VERSION 5.8 ;
BUSBITCHARS "[]" ;
DIVIDERCHAR "/" ;
UNITS
    DATABASE MICRONS 1000 ;
END UNITS

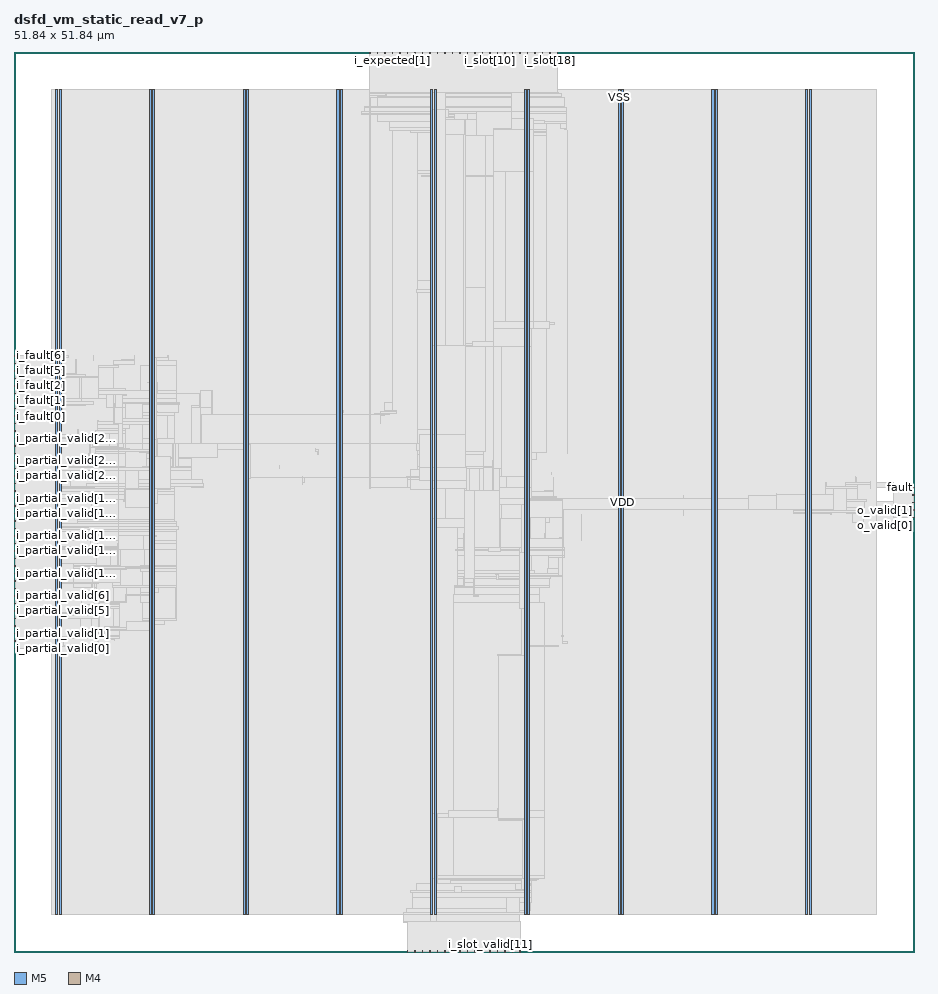
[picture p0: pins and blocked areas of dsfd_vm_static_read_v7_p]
MACRO dsfd_vm_static_read_v7_p
  FOREIGN dsfd_vm_static_read_v7_p 0 0 ;
  CLASS BLOCK ;
  SIZE 51.84 BY 51.84 ;
  PIN ck
    DIRECTION INPUT ;
    USE SIGNAL ;
    PORT
      LAYER M5 ;
        RECT  20.496 51.756 20.52 51.84 ;
    END
  END ck
  PIN fault
    DIRECTION OUTPUT ;
    USE SIGNAL ;
    PORT
      LAYER M4 ;
        RECT  51.756 26.736 51.84 26.76 ;
    END
  END fault
  PIN i_expected[0]
    DIRECTION INPUT ;
    USE SIGNAL ;
    PORT
      LAYER M5 ;
        RECT  21.36 51.756 21.384 51.84 ;
    END
  END i_expected[0]
  PIN i_expected[1]
    DIRECTION INPUT ;
    USE SIGNAL ;
    PORT
      LAYER M5 ;
        RECT  21.792 51.756 21.816 51.84 ;
    END
  END i_expected[1]
  PIN i_expected[2]
    DIRECTION INPUT ;
    USE SIGNAL ;
    PORT
      LAYER M5 ;
        RECT  22.224 51.756 22.248 51.84 ;
    END
  END i_expected[2]
  PIN i_expected[3]
    DIRECTION INPUT ;
    USE SIGNAL ;
    PORT
      LAYER M5 ;
        RECT  22.656 51.756 22.68 51.84 ;
    END
  END i_expected[3]
  PIN i_fault[0]
    DIRECTION INPUT ;
    USE SIGNAL ;
    PORT
      LAYER M4 ;
        RECT  0 31.296 0.084 31.32 ;
    END
  END i_fault[0]
  PIN i_fault[1]
    DIRECTION INPUT ;
    USE SIGNAL ;
    PORT
      LAYER M4 ;
        RECT  0 31.728 0.084 31.752 ;
    END
  END i_fault[1]
  PIN i_fault[2]
    DIRECTION INPUT ;
    USE SIGNAL ;
    PORT
      LAYER M4 ;
        RECT  0 32.16 0.084 32.184 ;
    END
  END i_fault[2]
  PIN i_fault[3]
    DIRECTION INPUT ;
    USE SIGNAL ;
    PORT
      LAYER M4 ;
        RECT  0 32.592 0.084 32.616 ;
    END
  END i_fault[3]
  PIN i_fault[4]
    DIRECTION INPUT ;
    USE SIGNAL ;
    PORT
      LAYER M4 ;
        RECT  0 33.024 0.084 33.048 ;
    END
  END i_fault[4]
  PIN i_fault[5]
    DIRECTION INPUT ;
    USE SIGNAL ;
    PORT
      LAYER M4 ;
        RECT  0 33.456 0.084 33.48 ;
    END
  END i_fault[5]
  PIN i_fault[6]
    DIRECTION INPUT ;
    USE SIGNAL ;
    PORT
      LAYER M4 ;
        RECT  0 33.888 0.084 33.912 ;
    END
  END i_fault[6]
  PIN i_fault[7]
    DIRECTION INPUT ;
    USE SIGNAL ;
    PORT
      LAYER M4 ;
        RECT  0 34.32 0.084 34.344 ;
    END
  END i_fault[7]
  PIN i_partial_valid[0]
    DIRECTION INPUT ;
    USE SIGNAL ;
    PORT
      LAYER M4 ;
        RECT  0 17.472 0.084 17.496 ;
    END
  END i_partial_valid[0]
  PIN i_partial_valid[10]
    DIRECTION INPUT ;
    USE SIGNAL ;
    PORT
      LAYER M4 ;
        RECT  0 21.792 0.084 21.816 ;
    END
  END i_partial_valid[10]
  PIN i_partial_valid[11]
    DIRECTION INPUT ;
    USE SIGNAL ;
    PORT
      LAYER M4 ;
        RECT  0 22.224 0.084 22.248 ;
    END
  END i_partial_valid[11]
  PIN i_partial_valid[12]
    DIRECTION INPUT ;
    USE SIGNAL ;
    PORT
      LAYER M4 ;
        RECT  0 22.656 0.084 22.68 ;
    END
  END i_partial_valid[12]
  PIN i_partial_valid[13]
    DIRECTION INPUT ;
    USE SIGNAL ;
    PORT
      LAYER M4 ;
        RECT  0 23.088 0.084 23.112 ;
    END
  END i_partial_valid[13]
  PIN i_partial_valid[14]
    DIRECTION INPUT ;
    USE SIGNAL ;
    PORT
      LAYER M4 ;
        RECT  0 23.52 0.084 23.544 ;
    END
  END i_partial_valid[14]
  PIN i_partial_valid[15]
    DIRECTION INPUT ;
    USE SIGNAL ;
    PORT
      LAYER M4 ;
        RECT  0 23.952 0.084 23.976 ;
    END
  END i_partial_valid[15]
  PIN i_partial_valid[16]
    DIRECTION INPUT ;
    USE SIGNAL ;
    PORT
      LAYER M4 ;
        RECT  0 24.384 0.084 24.408 ;
    END
  END i_partial_valid[16]
  PIN i_partial_valid[17]
    DIRECTION INPUT ;
    USE SIGNAL ;
    PORT
      LAYER M4 ;
        RECT  0 24.816 0.084 24.84 ;
    END
  END i_partial_valid[17]
  PIN i_partial_valid[18]
    DIRECTION INPUT ;
    USE SIGNAL ;
    PORT
      LAYER M4 ;
        RECT  0 25.248 0.084 25.272 ;
    END
  END i_partial_valid[18]
  PIN i_partial_valid[19]
    DIRECTION INPUT ;
    USE SIGNAL ;
    PORT
      LAYER M4 ;
        RECT  0 25.68 0.084 25.704 ;
    END
  END i_partial_valid[19]
  PIN i_partial_valid[1]
    DIRECTION INPUT ;
    USE SIGNAL ;
    PORT
      LAYER M4 ;
        RECT  0 17.904 0.084 17.928 ;
    END
  END i_partial_valid[1]
  PIN i_partial_valid[20]
    DIRECTION INPUT ;
    USE SIGNAL ;
    PORT
      LAYER M4 ;
        RECT  0 26.112 0.084 26.136 ;
    END
  END i_partial_valid[20]
  PIN i_partial_valid[21]
    DIRECTION INPUT ;
    USE SIGNAL ;
    PORT
      LAYER M4 ;
        RECT  0 26.544 0.084 26.568 ;
    END
  END i_partial_valid[21]
  PIN i_partial_valid[22]
    DIRECTION INPUT ;
    USE SIGNAL ;
    PORT
      LAYER M4 ;
        RECT  0 26.976 0.084 27 ;
    END
  END i_partial_valid[22]
  PIN i_partial_valid[23]
    DIRECTION INPUT ;
    USE SIGNAL ;
    PORT
      LAYER M4 ;
        RECT  0 27.408 0.084 27.432 ;
    END
  END i_partial_valid[23]
  PIN i_partial_valid[24]
    DIRECTION INPUT ;
    USE SIGNAL ;
    PORT
      LAYER M4 ;
        RECT  0 27.84 0.084 27.864 ;
    END
  END i_partial_valid[24]
  PIN i_partial_valid[25]
    DIRECTION INPUT ;
    USE SIGNAL ;
    PORT
      LAYER M4 ;
        RECT  0 28.272 0.084 28.296 ;
    END
  END i_partial_valid[25]
  PIN i_partial_valid[26]
    DIRECTION INPUT ;
    USE SIGNAL ;
    PORT
      LAYER M4 ;
        RECT  0 28.704 0.084 28.728 ;
    END
  END i_partial_valid[26]
  PIN i_partial_valid[27]
    DIRECTION INPUT ;
    USE SIGNAL ;
    PORT
      LAYER M4 ;
        RECT  0 29.136 0.084 29.16 ;
    END
  END i_partial_valid[27]
  PIN i_partial_valid[28]
    DIRECTION INPUT ;
    USE SIGNAL ;
    PORT
      LAYER M4 ;
        RECT  0 29.568 0.084 29.592 ;
    END
  END i_partial_valid[28]
  PIN i_partial_valid[29]
    DIRECTION INPUT ;
    USE SIGNAL ;
    PORT
      LAYER M4 ;
        RECT  0 30 0.084 30.024 ;
    END
  END i_partial_valid[29]
  PIN i_partial_valid[2]
    DIRECTION INPUT ;
    USE SIGNAL ;
    PORT
      LAYER M4 ;
        RECT  0 18.336 0.084 18.36 ;
    END
  END i_partial_valid[2]
  PIN i_partial_valid[30]
    DIRECTION INPUT ;
    USE SIGNAL ;
    PORT
      LAYER M4 ;
        RECT  0 30.432 0.084 30.456 ;
    END
  END i_partial_valid[30]
  PIN i_partial_valid[31]
    DIRECTION INPUT ;
    USE SIGNAL ;
    PORT
      LAYER M4 ;
        RECT  0 30.864 0.084 30.888 ;
    END
  END i_partial_valid[31]
  PIN i_partial_valid[3]
    DIRECTION INPUT ;
    USE SIGNAL ;
    PORT
      LAYER M4 ;
        RECT  0 18.768 0.084 18.792 ;
    END
  END i_partial_valid[3]
  PIN i_partial_valid[4]
    DIRECTION INPUT ;
    USE SIGNAL ;
    PORT
      LAYER M4 ;
        RECT  0 19.2 0.084 19.224 ;
    END
  END i_partial_valid[4]
  PIN i_partial_valid[5]
    DIRECTION INPUT ;
    USE SIGNAL ;
    PORT
      LAYER M4 ;
        RECT  0 19.632 0.084 19.656 ;
    END
  END i_partial_valid[5]
  PIN i_partial_valid[6]
    DIRECTION INPUT ;
    USE SIGNAL ;
    PORT
      LAYER M4 ;
        RECT  0 20.064 0.084 20.088 ;
    END
  END i_partial_valid[6]
  PIN i_partial_valid[7]
    DIRECTION INPUT ;
    USE SIGNAL ;
    PORT
      LAYER M4 ;
        RECT  0 20.496 0.084 20.52 ;
    END
  END i_partial_valid[7]
  PIN i_partial_valid[8]
    DIRECTION INPUT ;
    USE SIGNAL ;
    PORT
      LAYER M4 ;
        RECT  0 20.928 0.084 20.952 ;
    END
  END i_partial_valid[8]
  PIN i_partial_valid[9]
    DIRECTION INPUT ;
    USE SIGNAL ;
    PORT
      LAYER M4 ;
        RECT  0 21.36 0.084 21.384 ;
    END
  END i_partial_valid[9]
  PIN i_slot[0]
    DIRECTION INPUT ;
    USE SIGNAL ;
    PORT
      LAYER M5 ;
        RECT  23.088 51.756 23.112 51.84 ;
    END
  END i_slot[0]
  PIN i_slot[10]
    DIRECTION INPUT ;
    USE SIGNAL ;
    PORT
      LAYER M5 ;
        RECT  27.408 51.756 27.432 51.84 ;
    END
  END i_slot[10]
  PIN i_slot[11]
    DIRECTION INPUT ;
    USE SIGNAL ;
    PORT
      LAYER M5 ;
        RECT  27.84 51.756 27.864 51.84 ;
    END
  END i_slot[11]
  PIN i_slot[12]
    DIRECTION INPUT ;
    USE SIGNAL ;
    PORT
      LAYER M5 ;
        RECT  28.272 51.756 28.296 51.84 ;
    END
  END i_slot[12]
  PIN i_slot[13]
    DIRECTION INPUT ;
    USE SIGNAL ;
    PORT
      LAYER M5 ;
        RECT  28.704 51.756 28.728 51.84 ;
    END
  END i_slot[13]
  PIN i_slot[14]
    DIRECTION INPUT ;
    USE SIGNAL ;
    PORT
      LAYER M5 ;
        RECT  29.136 51.756 29.16 51.84 ;
    END
  END i_slot[14]
  PIN i_slot[15]
    DIRECTION INPUT ;
    USE SIGNAL ;
    PORT
      LAYER M5 ;
        RECT  29.568 51.756 29.592 51.84 ;
    END
  END i_slot[15]
  PIN i_slot[16]
    DIRECTION INPUT ;
    USE SIGNAL ;
    PORT
      LAYER M5 ;
        RECT  30 51.756 30.024 51.84 ;
    END
  END i_slot[16]
  PIN i_slot[17]
    DIRECTION INPUT ;
    USE SIGNAL ;
    PORT
      LAYER M5 ;
        RECT  30.432 51.756 30.456 51.84 ;
    END
  END i_slot[17]
  PIN i_slot[18]
    DIRECTION INPUT ;
    USE SIGNAL ;
    PORT
      LAYER M5 ;
        RECT  30.864 51.756 30.888 51.84 ;
    END
  END i_slot[18]
  PIN i_slot[19]
    DIRECTION INPUT ;
    USE SIGNAL ;
    PORT
      LAYER M5 ;
        RECT  31.296 51.756 31.32 51.84 ;
    END
  END i_slot[19]
  PIN i_slot[1]
    DIRECTION INPUT ;
    USE SIGNAL ;
    PORT
      LAYER M5 ;
        RECT  23.52 51.756 23.544 51.84 ;
    END
  END i_slot[1]
  PIN i_slot[2]
    DIRECTION INPUT ;
    USE SIGNAL ;
    PORT
      LAYER M5 ;
        RECT  23.952 51.756 23.976 51.84 ;
    END
  END i_slot[2]
  PIN i_slot[3]
    DIRECTION INPUT ;
    USE SIGNAL ;
    PORT
      LAYER M5 ;
        RECT  24.384 51.756 24.408 51.84 ;
    END
  END i_slot[3]
  PIN i_slot[4]
    DIRECTION INPUT ;
    USE SIGNAL ;
    PORT
      LAYER M5 ;
        RECT  24.816 51.756 24.84 51.84 ;
    END
  END i_slot[4]
  PIN i_slot[5]
    DIRECTION INPUT ;
    USE SIGNAL ;
    PORT
      LAYER M5 ;
        RECT  25.248 51.756 25.272 51.84 ;
    END
  END i_slot[5]
  PIN i_slot[6]
    DIRECTION INPUT ;
    USE SIGNAL ;
    PORT
      LAYER M5 ;
        RECT  25.68 51.756 25.704 51.84 ;
    END
  END i_slot[6]
  PIN i_slot[7]
    DIRECTION INPUT ;
    USE SIGNAL ;
    PORT
      LAYER M5 ;
        RECT  26.112 51.756 26.136 51.84 ;
    END
  END i_slot[7]
  PIN i_slot[8]
    DIRECTION INPUT ;
    USE SIGNAL ;
    PORT
      LAYER M5 ;
        RECT  26.544 51.756 26.568 51.84 ;
    END
  END i_slot[8]
  PIN i_slot[9]
    DIRECTION INPUT ;
    USE SIGNAL ;
    PORT
      LAYER M5 ;
        RECT  26.976 51.756 27 51.84 ;
    END
  END i_slot[9]
  PIN i_slot_valid[0]
    DIRECTION INPUT ;
    USE SIGNAL ;
    PORT
      LAYER M5 ;
        RECT  22.656 0 22.68 0.084 ;
    END
  END i_slot_valid[0]
  PIN i_slot_valid[10]
    DIRECTION INPUT ;
    USE SIGNAL ;
    PORT
      LAYER M5 ;
        RECT  26.976 0 27 0.084 ;
    END
  END i_slot_valid[10]
  PIN i_slot_valid[11]
    DIRECTION INPUT ;
    USE SIGNAL ;
    PORT
      LAYER M5 ;
        RECT  27.408 0 27.432 0.084 ;
    END
  END i_slot_valid[11]
  PIN i_slot_valid[12]
    DIRECTION INPUT ;
    USE SIGNAL ;
    PORT
      LAYER M5 ;
        RECT  27.84 0 27.864 0.084 ;
    END
  END i_slot_valid[12]
  PIN i_slot_valid[13]
    DIRECTION INPUT ;
    USE SIGNAL ;
    PORT
      LAYER M5 ;
        RECT  28.272 0 28.296 0.084 ;
    END
  END i_slot_valid[13]
  PIN i_slot_valid[14]
    DIRECTION INPUT ;
    USE SIGNAL ;
    PORT
      LAYER M5 ;
        RECT  28.704 0 28.728 0.084 ;
    END
  END i_slot_valid[14]
  PIN i_slot_valid[15]
    DIRECTION INPUT ;
    USE SIGNAL ;
    PORT
      LAYER M5 ;
        RECT  29.136 0 29.16 0.084 ;
    END
  END i_slot_valid[15]
  PIN i_slot_valid[1]
    DIRECTION INPUT ;
    USE SIGNAL ;
    PORT
      LAYER M5 ;
        RECT  23.088 0 23.112 0.084 ;
    END
  END i_slot_valid[1]
  PIN i_slot_valid[2]
    DIRECTION INPUT ;
    USE SIGNAL ;
    PORT
      LAYER M5 ;
        RECT  23.52 0 23.544 0.084 ;
    END
  END i_slot_valid[2]
  PIN i_slot_valid[3]
    DIRECTION INPUT ;
    USE SIGNAL ;
    PORT
      LAYER M5 ;
        RECT  23.952 0 23.976 0.084 ;
    END
  END i_slot_valid[3]
  PIN i_slot_valid[4]
    DIRECTION INPUT ;
    USE SIGNAL ;
    PORT
      LAYER M5 ;
        RECT  24.384 0 24.408 0.084 ;
    END
  END i_slot_valid[4]
  PIN i_slot_valid[5]
    DIRECTION INPUT ;
    USE SIGNAL ;
    PORT
      LAYER M5 ;
        RECT  24.816 0 24.84 0.084 ;
    END
  END i_slot_valid[5]
  PIN i_slot_valid[6]
    DIRECTION INPUT ;
    USE SIGNAL ;
    PORT
      LAYER M5 ;
        RECT  25.248 0 25.272 0.084 ;
    END
  END i_slot_valid[6]
  PIN i_slot_valid[7]
    DIRECTION INPUT ;
    USE SIGNAL ;
    PORT
      LAYER M5 ;
        RECT  25.68 0 25.704 0.084 ;
    END
  END i_slot_valid[7]
  PIN i_slot_valid[8]
    DIRECTION INPUT ;
    USE SIGNAL ;
    PORT
      LAYER M5 ;
        RECT  26.112 0 26.136 0.084 ;
    END
  END i_slot_valid[8]
  PIN i_slot_valid[9]
    DIRECTION INPUT ;
    USE SIGNAL ;
    PORT
      LAYER M5 ;
        RECT  26.544 0 26.568 0.084 ;
    END
  END i_slot_valid[9]
  PIN o_valid[0]
    DIRECTION OUTPUT ;
    USE SIGNAL ;
    PORT
      LAYER M4 ;
        RECT  51.756 25.008 51.84 25.032 ;
    END
  END o_valid[0]
  PIN o_valid[1]
    DIRECTION OUTPUT ;
    USE SIGNAL ;
    PORT
      LAYER M4 ;
        RECT  51.756 25.44 51.84 25.464 ;
    END
  END o_valid[1]
  PIN o_valid[2]
    DIRECTION OUTPUT ;
    USE SIGNAL ;
    PORT
      LAYER M4 ;
        RECT  51.756 25.872 51.84 25.896 ;
    END
  END o_valid[2]
  PIN o_valid[3]
    DIRECTION OUTPUT ;
    USE SIGNAL ;
    PORT
      LAYER M4 ;
        RECT  51.756 26.304 51.84 26.328 ;
    END
  END o_valid[3]
  PIN rst_n
    DIRECTION INPUT ;
    USE SIGNAL ;
    PORT
      LAYER M5 ;
        RECT  20.928 51.756 20.952 51.84 ;
    END
  END rst_n
  PIN VDD
    DIRECTION INOUT ;
    USE POWER ;
    PORT
      LAYER M5 ;
        RECT  45.792 2.151 45.912 49.689 ;
        RECT  40.392 2.151 40.512 49.689 ;
        RECT  34.992 2.151 35.112 49.689 ;
        RECT  29.592 2.151 29.712 49.689 ;
        RECT  24.192 2.151 24.312 49.689 ;
        RECT  18.792 2.151 18.912 49.689 ;
        RECT  13.392 2.151 13.512 49.689 ;
        RECT  7.992 2.151 8.112 49.689 ;
        RECT  2.592 2.151 2.712 49.689 ;
    END
  END VDD
  PIN VSS
    DIRECTION INOUT ;
    USE GROUND ;
    PORT
      LAYER M5 ;
        RECT  45.6 2.137 45.72 49.703 ;
        RECT  40.2 2.137 40.32 49.703 ;
        RECT  34.8 2.137 34.92 49.703 ;
        RECT  29.4 2.137 29.52 49.703 ;
        RECT  24 2.137 24.12 49.703 ;
        RECT  18.6 2.137 18.72 49.703 ;
        RECT  13.2 2.137 13.32 49.703 ;
        RECT  7.8 2.137 7.92 49.703 ;
        RECT  2.4 2.137 2.52 49.703 ;
    END
  END VSS
  # OT_OBS_CLOSED layer=M5 d_um=1.536 added=21
  OBS
    LAYER RVTN ;
     RECT  2.16 2.16 49.68 2.295 ;
     RECT  2.16 2.565 49.68 2.835 ;
     RECT  2.16 3.105 49.68 3.375 ;
     RECT  2.16 3.645 49.68 3.915 ;
     RECT  2.16 4.185 49.68 4.455 ;
     RECT  2.16 4.725 49.68 4.995 ;
     RECT  2.16 5.265 49.68 5.535 ;
     RECT  2.16 5.805 49.68 6.075 ;
     RECT  2.16 6.345 49.68 6.615 ;
     RECT  2.16 6.885 49.68 7.155 ;
     RECT  2.16 7.425 49.68 7.695 ;
     RECT  2.16 7.965 49.68 8.235 ;
     RECT  2.16 8.505 49.68 8.775 ;
     RECT  2.16 9.045 49.68 9.315 ;
     RECT  2.16 9.585 49.68 9.855 ;
     RECT  2.16 10.125 49.68 10.395 ;
     RECT  2.16 10.665 49.68 10.935 ;
     RECT  2.16 11.205 49.68 11.475 ;
     RECT  2.16 11.745 49.68 12.015 ;
     RECT  2.16 12.285 49.68 12.555 ;
     RECT  2.16 12.825 49.68 13.095 ;
     RECT  2.16 13.365 49.68 13.635 ;
     RECT  2.16 13.905 49.68 14.175 ;
     RECT  2.16 14.445 49.68 14.715 ;
     RECT  2.16 14.985 49.68 15.255 ;
     RECT  2.16 15.525 49.68 15.795 ;
     RECT  2.16 16.065 49.68 16.335 ;
     RECT  2.16 16.605 49.68 16.875 ;
     RECT  2.16 17.145 49.68 17.415 ;
     RECT  2.16 17.685 49.68 17.955 ;
     RECT  2.16 18.225 49.68 18.495 ;
     RECT  2.16 18.765 49.68 19.035 ;
     RECT  2.16 19.305 49.68 19.575 ;
     RECT  2.16 19.845 49.68 20.115 ;
     RECT  2.16 20.385 49.68 20.655 ;
     RECT  2.16 20.925 49.68 21.195 ;
     RECT  2.16 21.465 49.68 21.735 ;
     RECT  2.16 22.005 49.68 22.275 ;
     RECT  2.16 22.545 49.68 22.815 ;
     RECT  2.16 23.085 49.68 23.355 ;
     RECT  2.16 23.625 49.68 23.895 ;
     RECT  2.16 24.165 49.68 24.435 ;
     RECT  2.16 24.705 49.68 24.975 ;
     RECT  2.16 25.245 49.68 25.515 ;
     RECT  2.16 25.785 49.68 26.055 ;
     RECT  2.16 26.325 49.68 26.595 ;
     RECT  2.16 26.865 49.68 27.135 ;
     RECT  2.16 27.405 49.68 27.675 ;
     RECT  2.16 27.945 49.68 28.215 ;
     RECT  2.16 28.485 49.68 28.755 ;
     RECT  2.16 29.025 49.68 29.295 ;
     RECT  2.16 29.565 49.68 29.835 ;
     RECT  2.16 30.105 49.68 30.375 ;
     RECT  2.16 30.645 49.68 30.915 ;
     RECT  2.16 31.185 49.68 31.455 ;
     RECT  2.16 31.725 49.68 31.995 ;
     RECT  2.16 32.265 49.68 32.535 ;
     RECT  2.16 32.805 49.68 33.075 ;
     RECT  2.16 33.345 49.68 33.615 ;
     RECT  2.16 33.885 49.68 34.155 ;
     RECT  2.16 34.425 49.68 34.695 ;
     RECT  2.16 34.965 49.68 35.235 ;
     RECT  2.16 35.505 49.68 35.775 ;
     RECT  2.16 36.045 49.68 36.315 ;
     RECT  2.16 36.585 49.68 36.855 ;
     RECT  2.16 37.125 49.68 37.395 ;
     RECT  2.16 37.665 49.68 37.935 ;
     RECT  2.16 38.205 49.68 38.475 ;
     RECT  2.16 38.745 49.68 39.015 ;
     RECT  2.16 39.285 49.68 39.555 ;
     RECT  2.16 39.825 49.68 40.095 ;
     RECT  2.16 40.365 49.68 40.635 ;
     RECT  2.16 40.905 49.68 41.175 ;
     RECT  2.16 41.445 49.68 41.715 ;
     RECT  2.16 41.985 49.68 42.255 ;
     RECT  2.16 42.525 49.68 42.795 ;
     RECT  2.16 43.065 49.68 43.335 ;
     RECT  2.16 43.605 49.68 43.875 ;
     RECT  2.16 44.145 49.68 44.415 ;
     RECT  2.16 44.685 49.68 44.955 ;
     RECT  2.16 45.225 49.68 45.495 ;
     RECT  2.16 45.765 49.68 46.035 ;
     RECT  2.16 46.305 49.68 46.575 ;
     RECT  2.16 46.845 49.68 47.115 ;
     RECT  2.16 47.385 49.68 47.655 ;
     RECT  2.16 47.925 49.68 48.195 ;
     RECT  2.16 48.465 49.68 48.735 ;
     RECT  2.16 49.005 49.68 49.275 ;
     RECT  2.16 49.545 49.68 49.68 ;
    LAYER RVTP ;
     RECT  2.16 2.295 49.68 2.565 ;
     RECT  2.16 2.835 49.68 3.105 ;
     RECT  2.16 3.375 49.68 3.645 ;
     RECT  2.16 3.915 49.68 4.185 ;
     RECT  2.16 4.455 49.68 4.725 ;
     RECT  2.16 4.995 49.68 5.265 ;
     RECT  2.16 5.535 49.68 5.805 ;
     RECT  2.16 6.075 49.68 6.345 ;
     RECT  2.16 6.615 49.68 6.885 ;
     RECT  2.16 7.155 49.68 7.425 ;
     RECT  2.16 7.695 49.68 7.965 ;
     RECT  2.16 8.235 49.68 8.505 ;
     RECT  2.16 8.775 49.68 9.045 ;
     RECT  2.16 9.315 49.68 9.585 ;
     RECT  2.16 9.855 49.68 10.125 ;
     RECT  2.16 10.395 49.68 10.665 ;
     RECT  2.16 10.935 49.68 11.205 ;
     RECT  2.16 11.475 49.68 11.745 ;
     RECT  2.16 12.015 49.68 12.285 ;
     RECT  2.16 12.555 49.68 12.825 ;
     RECT  2.16 13.095 49.68 13.365 ;
     RECT  2.16 13.635 49.68 13.905 ;
     RECT  2.16 14.175 49.68 14.445 ;
     RECT  2.16 14.715 49.68 14.985 ;
     RECT  2.16 15.255 49.68 15.525 ;
     RECT  2.16 15.795 49.68 16.065 ;
     RECT  2.16 16.335 49.68 16.605 ;
     RECT  2.16 16.875 49.68 17.145 ;
     RECT  2.16 17.415 49.68 17.685 ;
     RECT  2.16 17.955 49.68 18.225 ;
     RECT  2.16 18.495 49.68 18.765 ;
     RECT  2.16 19.035 49.68 19.305 ;
     RECT  2.16 19.575 49.68 19.845 ;
     RECT  2.16 20.115 49.68 20.385 ;
     RECT  2.16 20.655 49.68 20.925 ;
     RECT  2.16 21.195 49.68 21.465 ;
     RECT  2.16 21.735 49.68 22.005 ;
     RECT  2.16 22.275 49.68 22.545 ;
     RECT  2.16 22.815 49.68 23.085 ;
     RECT  2.16 23.355 49.68 23.625 ;
     RECT  2.16 23.895 49.68 24.165 ;
     RECT  2.16 24.435 49.68 24.705 ;
     RECT  2.16 24.975 49.68 25.245 ;
     RECT  2.16 25.515 49.68 25.785 ;
     RECT  2.16 26.055 49.68 26.325 ;
     RECT  2.16 26.595 49.68 26.865 ;
     RECT  2.16 27.135 49.68 27.405 ;
     RECT  2.16 27.675 49.68 27.945 ;
     RECT  2.16 28.215 49.68 28.485 ;
     RECT  2.16 28.755 49.68 29.025 ;
     RECT  2.16 29.295 49.68 29.565 ;
     RECT  2.16 29.835 49.68 30.105 ;
     RECT  2.16 30.375 49.68 30.645 ;
     RECT  2.16 30.915 49.68 31.185 ;
     RECT  2.16 31.455 49.68 31.725 ;
     RECT  2.16 31.995 49.68 32.265 ;
     RECT  2.16 32.535 49.68 32.805 ;
     RECT  2.16 33.075 49.68 33.345 ;
     RECT  2.16 33.615 49.68 33.885 ;
     RECT  2.16 34.155 49.68 34.425 ;
     RECT  2.16 34.695 49.68 34.965 ;
     RECT  2.16 35.235 49.68 35.505 ;
     RECT  2.16 35.775 49.68 36.045 ;
     RECT  2.16 36.315 49.68 36.585 ;
     RECT  2.16 36.855 49.68 37.125 ;
     RECT  2.16 37.395 49.68 37.665 ;
     RECT  2.16 37.935 49.68 38.205 ;
     RECT  2.16 38.475 49.68 38.745 ;
     RECT  2.16 39.015 49.68 39.285 ;
     RECT  2.16 39.555 49.68 39.825 ;
     RECT  2.16 40.095 49.68 40.365 ;
     RECT  2.16 40.635 49.68 40.905 ;
     RECT  2.16 41.175 49.68 41.445 ;
     RECT  2.16 41.715 49.68 41.985 ;
     RECT  2.16 42.255 49.68 42.525 ;
     RECT  2.16 42.795 49.68 43.065 ;
     RECT  2.16 43.335 49.68 43.605 ;
     RECT  2.16 43.875 49.68 44.145 ;
     RECT  2.16 44.415 49.68 44.685 ;
     RECT  2.16 44.955 49.68 45.225 ;
     RECT  2.16 45.495 49.68 45.765 ;
     RECT  2.16 46.035 49.68 46.305 ;
     RECT  2.16 46.575 49.68 46.845 ;
     RECT  2.16 47.115 49.68 47.385 ;
     RECT  2.16 47.655 49.68 47.925 ;
     RECT  2.16 48.195 49.68 48.465 ;
     RECT  2.16 48.735 49.68 49.005 ;
     RECT  2.16 49.275 49.68 49.545 ;
    LAYER M1 ;
     RECT  2.16 2.151 49.68 49.689 ;
    LAYER M2 ;
     RECT  0.535 22.212 2.16 22.23 ;
     RECT  2.16 2.151 49.68 49.689 ;
     RECT  49.68 26.766 50.675 27.054 ;
     RECT  49.68 24.786 50.711 25.974 ;
     RECT  50.675 26.766 50.711 26.784 ;
    LAYER M3 ;
     RECT  23.94 0.571 23.958 1.723 ;
     RECT  25.668 0.571 25.686 1.723 ;
     RECT  22.428 1.723 29.142 2.143 ;
     RECT  22.428 2.143 29.505 2.255 ;
     RECT  29.088 2.255 29.505 2.371 ;
     RECT  2.415 2.143 2.505 2.413 ;
     RECT  7.815 2.143 7.905 2.413 ;
     RECT  13.215 2.143 13.305 2.413 ;
     RECT  18.615 2.143 18.705 2.413 ;
     RECT  34.815 2.143 34.905 2.413 ;
     RECT  40.215 2.143 40.305 2.413 ;
     RECT  45.615 2.143 45.705 2.413 ;
     RECT  22.608 2.255 28.35 2.489 ;
     RECT  29.088 2.371 29.754 2.839 ;
     RECT  22.932 2.489 28.35 3.145 ;
     RECT  29.088 2.839 29.826 3.145 ;
     RECT  22.932 3.145 29.826 3.451 ;
     RECT  22.824 3.451 29.826 3.569 ;
     RECT  23.184 3.569 29.826 3.947 ;
     RECT  23.616 3.947 29.826 3.965 ;
     RECT  24.015 3.965 29.826 4.117 ;
     RECT  24.015 4.117 30.078 4.153 ;
     RECT  24.015 4.153 30.186 4.261 ;
     RECT  24.015 4.261 30.546 4.415 ;
     RECT  25.308 4.415 30.546 7.723 ;
     RECT  25.02 7.723 30.546 8.159 ;
     RECT  2.415 2.413 2.697 17.455 ;
     RECT  2.304 17.455 2.697 17.501 ;
     RECT  2.415 17.501 2.697 17.608 ;
     RECT  4.428 17.581 4.446 17.611 ;
     RECT  4.428 17.611 4.842 17.617 ;
     RECT  31.356 17.608 31.374 17.645 ;
     RECT  2.415 17.608 3.294 17.653 ;
     RECT  4.068 17.617 4.842 17.653 ;
     RECT  31.572 17.761 31.878 17.879 ;
     RECT  5.796 17.959 5.814 17.995 ;
     RECT  2.415 17.653 4.842 18.031 ;
     RECT  5.616 17.995 5.814 18.031 ;
     RECT  2.415 18.031 6.066 18.185 ;
     RECT  3.816 18.185 6.066 18.221 ;
     RECT  31.572 17.879 31.59 18.221 ;
     RECT  2.415 18.185 2.697 18.331 ;
     RECT  2.304 18.331 2.697 18.455 ;
     RECT  7.815 2.413 8.097 18.499 ;
     RECT  5.22 18.221 6.066 18.523 ;
     RECT  7.416 18.499 8.097 18.535 ;
     RECT  5.22 18.523 6.462 18.571 ;
     RECT  7.308 18.535 8.097 18.571 ;
     RECT  5.22 18.571 8.097 18.689 ;
     RECT  5.22 18.689 6.066 18.725 ;
     RECT  7.416 18.689 8.097 18.841 ;
     RECT  7.416 18.841 8.658 19.075 ;
     RECT  7.416 19.075 8.946 19.111 ;
     RECT  2.415 18.455 2.697 19.195 ;
     RECT  3.816 18.221 4.446 19.201 ;
     RECT  7.416 19.111 9.342 19.229 ;
     RECT  2.304 19.195 2.697 19.237 ;
     RECT  3.816 19.201 4.842 19.237 ;
     RECT  2.304 19.237 4.842 19.499 ;
     RECT  2.304 19.499 3.15 19.535 ;
     RECT  5.724 18.725 6.066 19.777 ;
     RECT  3.888 19.499 4.842 19.921 ;
     RECT  5.58 19.777 6.066 19.921 ;
     RECT  3.888 19.921 6.102 20.039 ;
     RECT  5.58 20.039 6.102 20.075 ;
     RECT  25.308 8.159 30.546 20.111 ;
     RECT  5.724 20.075 6.102 20.149 ;
     RECT  7.416 19.229 8.097 20.155 ;
     RECT  25.308 20.111 30.258 20.579 ;
     RECT  7.308 20.155 8.097 20.731 ;
     RECT  3.888 20.039 4.734 21.001 ;
     RECT  5.724 20.149 6.462 21.001 ;
     RECT  7.308 20.731 8.334 21.001 ;
     RECT  9.324 19.229 9.342 21.001 ;
     RECT  25.38 20.579 30.258 21.001 ;
     RECT  25.38 21.001 30.87 21.101 ;
     RECT  5.688 21.001 9.342 21.119 ;
     RECT  2.304 19.535 2.697 21.211 ;
     RECT  3.42 21.001 4.734 21.211 ;
     RECT  2.304 21.211 4.878 21.263 ;
     RECT  3.42 21.263 4.878 21.271 ;
     RECT  5.688 21.119 6.138 21.271 ;
     RECT  25.56 21.101 30.87 21.541 ;
     RECT  25.56 21.541 30.906 21.631 ;
     RECT  25.56 21.631 31.374 21.803 ;
     RECT  7.416 21.119 9.342 21.937 ;
     RECT  25.56 21.803 29.97 22.001 ;
     RECT  3.42 21.271 6.138 22.009 ;
     RECT  30.744 21.803 31.374 22.073 ;
     RECT  3.42 22.009 6.462 22.081 ;
     RECT  7.272 21.937 9.342 22.081 ;
     RECT  3.42 22.081 9.342 22.199 ;
     RECT  3.42 22.199 6.462 22.205 ;
     RECT  3.42 22.205 6.138 22.235 ;
     RECT  7.272 22.199 9.342 22.235 ;
     RECT  0.54 22.207 0.558 22.253 ;
     RECT  2.304 21.263 2.697 22.351 ;
     RECT  3.42 22.235 4.734 22.351 ;
     RECT  30.78 22.073 31.374 22.711 ;
     RECT  25.56 22.001 29.79 22.819 ;
     RECT  30.78 22.711 31.698 22.819 ;
     RECT  25.56 22.819 31.698 23.125 ;
     RECT  2.304 22.351 4.734 23.161 ;
     RECT  5.544 22.235 6.138 23.161 ;
     RECT  7.488 22.235 9.342 23.161 ;
     RECT  25.452 23.125 31.698 23.165 ;
     RECT  2.304 23.161 6.138 23.251 ;
     RECT  25.56 23.165 31.698 23.315 ;
     RECT  2.304 23.251 6.21 23.323 ;
     RECT  7.452 23.161 9.342 23.557 ;
     RECT  2.304 23.323 6.462 23.701 ;
     RECT  7.272 23.557 9.342 23.701 ;
     RECT  25.56 23.315 31.626 23.819 ;
     RECT  31.428 23.819 31.626 23.855 ;
     RECT  30.564 23.819 30.618 24.089 ;
     RECT  2.304 23.701 9.342 24.241 ;
     RECT  2.304 24.241 9.378 24.331 ;
     RECT  24.015 4.415 24.297 24.475 ;
     RECT  25.56 23.819 29.754 24.475 ;
     RECT  2.304 24.331 9.486 24.503 ;
     RECT  2.304 24.503 9.378 24.665 ;
     RECT  48.996 24.601 49.014 24.701 ;
     RECT  30.6 24.089 30.618 24.745 ;
     RECT  3.672 24.665 9.378 24.809 ;
     RECT  3.672 24.809 9.234 24.899 ;
     RECT  2.304 24.665 2.697 24.935 ;
     RECT  3.672 24.899 3.69 24.971 ;
     RECT  24.015 24.475 29.754 25.015 ;
     RECT  30.6 24.745 30.87 25.015 ;
     RECT  24.015 25.015 30.87 25.037 ;
     RECT  25.128 25.037 30.87 25.051 ;
     RECT  31.608 23.855 31.626 25.051 ;
     RECT  32.688 23.701 32.706 25.205 ;
     RECT  45.615 2.413 45.897 25.249 ;
     RECT  47.052 25.177 47.07 25.249 ;
     RECT  48.312 24.745 48.906 25.249 ;
     RECT  44.892 25.249 47.07 25.321 ;
     RECT  47.952 25.249 48.906 25.321 ;
     RECT  44.892 25.321 48.906 25.439 ;
     RECT  44.892 25.439 47.178 25.52 ;
     RECT  47.952 25.439 48.906 25.591 ;
     RECT  2.415 24.935 2.697 25.675 ;
     RECT  32.544 25.591 32.562 25.709 ;
     RECT  2.304 25.675 2.697 25.745 ;
     RECT  47.952 25.591 49.014 25.951 ;
     RECT  25.128 25.051 31.626 25.979 ;
     RECT  50.688 24.781 50.706 25.979 ;
     RECT  47.952 25.951 49.122 26.051 ;
     RECT  42.768 25.861 43.29 26.087 ;
     RECT  44.892 25.52 47.034 26.095 ;
     RECT  2.415 25.745 2.697 26.131 ;
     RECT  25.128 25.979 31.23 26.131 ;
     RECT  24.015 25.037 24.297 26.155 ;
     RECT  25.056 26.131 31.23 26.155 ;
     RECT  24.015 26.155 31.23 26.249 ;
     RECT  43.164 26.087 43.182 26.249 ;
     RECT  44.784 26.095 47.034 26.249 ;
     RECT  38.556 25.141 38.574 26.285 ;
     RECT  42.3 26.095 42.318 26.285 ;
     RECT  44.784 26.249 45.897 26.285 ;
     RECT  44.892 26.285 45.897 26.321 ;
     RECT  46.764 26.249 47.034 26.347 ;
     RECT  2.415 26.131 3.294 26.365 ;
     RECT  4.464 24.899 9.234 26.365 ;
     RECT  43.92 26.251 43.938 26.381 ;
     RECT  24.015 26.249 31.086 26.519 ;
     RECT  2.415 26.365 9.234 26.527 ;
     RECT  24.015 26.519 29.697 26.555 ;
     RECT  30.528 26.519 31.086 26.555 ;
     RECT  2.304 26.527 9.234 26.669 ;
     RECT  46.764 26.347 47.214 26.671 ;
     RECT  47.952 26.051 48.582 26.671 ;
     RECT  50.652 26.299 50.67 26.731 ;
     RECT  46.764 26.671 48.582 26.789 ;
     RECT  50.652 26.731 50.706 26.789 ;
     RECT  7.164 26.669 9.234 26.797 ;
     RECT  10.224 26.761 10.926 26.797 ;
     RECT  2.304 26.669 6.426 26.825 ;
     RECT  47.88 26.789 48.582 26.905 ;
     RECT  49.32 26.671 49.338 26.905 ;
     RECT  4.176 26.825 6.426 26.969 ;
     RECT  7.164 26.797 10.926 26.969 ;
     RECT  16.596 26.905 16.614 27.031 ;
     RECT  46.764 26.789 46.782 27.059 ;
     RECT  47.88 26.905 49.338 27.059 ;
     RECT  50.652 26.789 50.67 27.059 ;
     RECT  2.304 26.825 3.258 27.095 ;
     RECT  49.32 27.059 49.338 27.095 ;
     RECT  22.824 26.635 22.842 27.163 ;
     RECT  24.015 26.555 27.27 27.163 ;
     RECT  7.164 26.969 10.854 27.239 ;
     RECT  22.824 27.163 27.27 27.307 ;
     RECT  16.596 27.031 16.758 27.329 ;
     RECT  31.068 26.555 31.086 27.329 ;
     RECT  48.456 27.059 48.546 27.329 ;
     RECT  28.008 26.555 29.697 27.337 ;
     RECT  16.596 27.329 16.614 27.365 ;
     RECT  22.608 27.307 27.27 27.365 ;
     RECT  48.456 27.329 48.474 27.365 ;
     RECT  22.824 27.365 27.27 27.373 ;
     RECT  28.008 27.337 29.826 27.373 ;
     RECT  30.96 27.481 30.978 27.599 ;
     RECT  4.572 26.969 6.426 27.715 ;
     RECT  2.34 27.095 3.258 27.751 ;
     RECT  4.068 27.715 6.426 27.751 ;
     RECT  7.164 27.239 10.242 27.751 ;
     RECT  22.824 27.373 29.826 27.779 ;
     RECT  13.215 2.413 13.497 27.841 ;
     RECT  2.34 27.751 10.242 27.905 ;
     RECT  13.215 27.841 13.554 27.917 ;
     RECT  2.34 27.905 6.426 27.941 ;
     RECT  7.416 27.905 10.242 27.941 ;
     RECT  23.22 27.779 29.826 27.941 ;
     RECT  15.264 27.877 15.282 28.049 ;
     RECT  28.008 27.941 29.826 28.049 ;
     RECT  29.16 28.049 29.826 28.247 ;
     RECT  2.34 27.941 2.697 28.267 ;
     RECT  29.232 28.247 29.826 28.283 ;
     RECT  28.008 28.049 28.386 28.301 ;
     RECT  28.008 28.301 28.278 28.319 ;
     RECT  29.415 28.283 29.826 28.381 ;
     RECT  7.632 27.941 10.242 28.409 ;
     RECT  23.22 27.941 27.018 28.679 ;
     RECT  4.284 27.941 6.426 28.715 ;
     RECT  7.632 28.409 9.414 28.715 ;
     RECT  7.632 28.715 9.234 28.759 ;
     RECT  7.416 28.759 9.234 28.795 ;
     RECT  29.415 28.381 30.078 28.795 ;
     RECT  4.68 28.715 6.426 28.831 ;
     RECT  7.236 28.795 9.234 28.831 ;
     RECT  17.496 28.651 17.514 28.831 ;
     RECT  25.956 28.679 27.018 28.831 ;
     RECT  4.68 28.831 9.234 28.949 ;
     RECT  17.352 28.831 17.514 28.949 ;
     RECT  23.22 28.679 25.146 28.949 ;
     RECT  4.68 28.949 6.642 28.985 ;
     RECT  17.352 28.949 17.37 28.985 ;
     RECT  5.472 28.985 6.642 29.021 ;
     RECT  2.304 28.267 2.697 29.255 ;
     RECT  11.7 28.507 11.718 29.309 ;
     RECT  4.68 28.985 4.698 29.497 ;
     RECT  7.416 28.949 9.234 29.549 ;
     RECT  2.415 29.255 2.697 29.569 ;
     RECT  2.415 29.569 3.33 29.641 ;
     RECT  4.14 29.497 4.698 29.641 ;
     RECT  2.415 29.641 4.698 29.795 ;
     RECT  4.5 29.795 4.698 29.831 ;
     RECT  4.68 29.831 4.698 29.875 ;
     RECT  5.472 29.021 6.426 29.875 ;
     RECT  4.68 29.875 6.426 30.029 ;
     RECT  3.672 29.795 3.69 30.101 ;
     RECT  23.256 28.949 25.146 30.101 ;
     RECT  4.824 30.029 6.426 30.145 ;
     RECT  4.824 30.145 6.642 30.379 ;
     RECT  7.416 29.549 8.097 30.379 ;
     RECT  2.415 29.795 2.697 30.415 ;
     RECT  2.304 30.415 2.697 30.461 ;
     RECT  4.824 30.379 8.097 30.569 ;
     RECT  4.824 30.569 4.842 30.605 ;
     RECT  5.76 30.569 8.097 30.749 ;
     RECT  7.416 30.749 8.097 30.919 ;
     RECT  8.856 29.549 9.234 30.919 ;
     RECT  21.096 30.451 21.114 30.919 ;
     RECT  21.096 30.919 21.33 30.955 ;
     RECT  20.772 30.955 21.618 30.991 ;
     RECT  20.772 30.991 22.05 30.992 ;
     RECT  7.416 30.919 9.234 31.081 ;
     RECT  18.615 2.413 18.897 31.081 ;
     RECT  21.096 30.992 22.05 31.145 ;
     RECT  18.615 31.081 18.954 31.217 ;
     RECT  21.312 31.145 22.05 31.217 ;
     RECT  2.415 30.461 2.697 31.225 ;
     RECT  2.304 31.225 2.697 31.261 ;
     RECT  5.76 30.749 6.426 31.339 ;
     RECT  10.224 28.409 10.242 31.339 ;
     RECT  10.224 31.339 10.782 31.487 ;
     RECT  2.304 31.261 2.79 31.495 ;
     RECT  3.888 31.459 3.906 31.495 ;
     RECT  2.304 31.495 4.122 31.531 ;
     RECT  7.416 31.081 9.45 31.531 ;
     RECT  5.364 31.339 6.426 31.621 ;
     RECT  7.416 31.531 9.522 31.621 ;
     RECT  5.364 31.621 9.522 31.649 ;
     RECT  21.312 31.217 21.798 31.649 ;
     RECT  2.304 31.531 4.554 31.721 ;
     RECT  5.364 31.649 9.378 31.867 ;
     RECT  10.764 31.487 10.782 31.867 ;
     RECT  2.304 31.721 3.906 31.901 ;
     RECT  10.764 31.867 11.394 31.919 ;
     RECT  10.764 31.919 10.782 32.333 ;
     RECT  4.86 31.867 9.378 32.369 ;
     RECT  4.86 32.369 6.426 32.459 ;
     RECT  2.304 31.901 2.697 33.109 ;
     RECT  3.744 31.901 3.906 33.109 ;
     RECT  2.304 33.109 3.906 33.115 ;
     RECT  2.304 33.115 4.122 33.269 ;
     RECT  2.304 33.269 3.582 33.305 ;
     RECT  4.86 32.459 5.742 33.643 ;
     RECT  4.86 33.643 6.03 33.809 ;
     RECT  7.308 32.369 9.378 33.809 ;
     RECT  5.724 33.809 6.03 33.853 ;
     RECT  6.84 33.817 6.966 33.853 ;
     RECT  2.304 33.305 2.697 33.953 ;
     RECT  5.724 33.853 6.966 34.079 ;
     RECT  7.815 33.809 9.378 34.079 ;
     RECT  3.564 33.305 3.582 34.115 ;
     RECT  6.192 34.079 6.966 34.115 ;
     RECT  6.192 34.115 6.21 34.151 ;
     RECT  2.412 33.953 2.697 34.231 ;
     RECT  7.815 34.079 8.874 34.253 ;
     RECT  2.412 34.231 3.114 34.349 ;
     RECT  6.948 34.115 6.966 34.349 ;
     RECT  8.856 34.253 8.874 34.349 ;
     RECT  2.412 34.349 2.697 34.385 ;
     RECT  4.572 34.051 4.59 34.385 ;
     RECT  25.956 28.831 27.162 35.035 ;
     RECT  28.008 28.319 28.026 35.035 ;
     RECT  25.956 35.035 28.026 35.075 ;
     RECT  29.415 28.795 30.654 35.899 ;
     RECT  29.415 35.899 30.834 36.121 ;
     RECT  29.415 36.121 31.122 36.239 ;
     RECT  29.415 36.239 30.834 36.317 ;
     RECT  23.256 30.101 24.354 38.011 ;
     RECT  23.184 38.011 24.354 38.165 ;
     RECT  25.956 35.075 27.162 38.273 ;
     RECT  23.22 38.165 24.354 38.669 ;
     RECT  28.008 35.075 28.026 44.587 ;
     RECT  28.008 44.587 28.278 44.761 ;
     RECT  23.22 38.669 24.297 44.851 ;
     RECT  25.092 30.101 25.146 44.851 ;
     RECT  23.22 44.851 25.146 45.005 ;
     RECT  28.008 44.761 28.602 45.005 ;
     RECT  29.415 36.317 30.654 47.011 ;
     RECT  23.22 45.005 24.297 47.191 ;
     RECT  29.016 47.011 30.654 47.191 ;
     RECT  28.008 45.005 28.026 47.281 ;
     RECT  28.8 47.191 30.654 47.281 ;
     RECT  21.78 31.649 21.798 47.317 ;
     RECT  22.824 47.191 24.297 47.317 ;
     RECT  25.092 45.005 25.146 47.317 ;
     RECT  25.956 38.273 25.974 47.317 ;
     RECT  27.144 38.273 27.162 47.323 ;
     RECT  31.86 28.723 31.878 47.345 ;
     RECT  27.072 47.323 27.162 47.371 ;
     RECT  28.008 47.281 30.654 47.371 ;
     RECT  31.788 47.353 31.806 47.389 ;
     RECT  31.68 47.389 31.806 47.425 ;
     RECT  25.092 47.317 25.974 47.489 ;
     RECT  21.6 47.317 24.297 47.515 ;
     RECT  25.092 47.489 25.398 47.515 ;
     RECT  27.072 47.371 30.654 47.707 ;
     RECT  31.5 47.425 31.806 47.707 ;
     RECT  21.6 47.515 25.398 47.821 ;
     RECT  26.136 47.731 26.298 47.821 ;
     RECT  27.072 47.707 31.806 47.821 ;
     RECT  20.916 47.821 25.398 48.235 ;
     RECT  20.016 48.235 25.398 48.271 ;
     RECT  26.136 47.821 31.806 48.271 ;
     RECT  20.016 48.271 31.806 48.425 ;
     RECT  20.16 48.425 31.806 48.659 ;
     RECT  20.16 48.659 31.698 48.695 ;
     RECT  20.952 48.695 31.698 49.199 ;
     RECT  21.06 49.199 31.554 49.277 ;
     RECT  2.415 34.385 2.697 49.427 ;
     RECT  7.815 34.253 8.097 49.427 ;
     RECT  13.215 27.917 13.497 49.427 ;
     RECT  18.615 31.217 18.897 49.427 ;
     RECT  34.815 2.413 35.097 49.427 ;
     RECT  40.215 2.413 40.497 49.427 ;
     RECT  45.615 26.321 45.897 49.427 ;
     RECT  21.096 49.277 31.554 49.469 ;
     RECT  21.348 49.469 31.338 49.517 ;
     RECT  26.856 49.517 30.834 49.565 ;
     RECT  21.348 49.517 21.366 49.577 ;
     RECT  22.104 49.517 25.902 49.577 ;
     RECT  26.856 49.565 26.874 49.577 ;
     RECT  27.72 49.565 30.438 49.577 ;
     RECT  2.415 49.427 2.505 49.697 ;
     RECT  7.815 49.427 7.905 49.697 ;
     RECT  13.215 49.427 13.305 49.697 ;
     RECT  18.615 49.427 18.705 49.697 ;
     RECT  23.832 49.577 24.105 49.697 ;
     RECT  34.815 49.427 34.905 49.697 ;
     RECT  40.215 49.427 40.305 49.697 ;
     RECT  45.615 49.427 45.705 49.697 ;
     RECT  29.016 49.577 29.574 49.805 ;
     RECT  22.104 49.577 22.122 50.765 ;
     RECT  23.832 49.697 23.85 50.765 ;
     RECT  25.632 49.577 25.65 50.765 ;
     RECT  29.016 49.805 29.034 50.765 ;
    LAYER M4 ;
     RECT  0.06 17.472 2.408 34.344 ;
     RECT  2.408 2.148 2.512 49.692 ;
     RECT  2.512 2.418 2.704 49.422 ;
     RECT  2.704 17.616 2.837 17.928 ;
     RECT  2.704 24.48 4.277 24.504 ;
     RECT  4.316 28.272 4.357 28.296 ;
     RECT  2.704 29.616 4.357 29.64 ;
     RECT  2.704 23.328 4.381 23.352 ;
     RECT  4.357 28.272 4.403 29.64 ;
     RECT  2.704 21.216 4.46 21.24 ;
     RECT  4.403 29.088 4.529 29.64 ;
     RECT  2.704 19.392 4.561 19.416 ;
     RECT  4.46 20.64 4.561 21.24 ;
     RECT  2.704 26.736 4.637 26.76 ;
     RECT  4.561 19.392 4.645 21.24 ;
     RECT  2.837 17.616 4.813 17.64 ;
     RECT  4.381 23.328 4.817 23.832 ;
     RECT  2.704 31.872 4.849 31.896 ;
     RECT  2.704 33.12 4.849 33.144 ;
     RECT  4.813 17.616 4.853 18.216 ;
     RECT  4.853 18.192 4.885 18.216 ;
     RECT  4.645 19.392 4.885 20.184 ;
     RECT  4.645 21.216 4.889 21.24 ;
     RECT  4.849 33.12 4.889 33.672 ;
     RECT  4.885 18.192 4.931 20.184 ;
     RECT  4.849 31.872 5.353 32.088 ;
     RECT  5.353 31.344 5.749 32.088 ;
     RECT  5.749 30.432 5.836 32.088 ;
     RECT  4.501 22.224 5.948 22.248 ;
     RECT  4.817 23.328 5.948 23.352 ;
     RECT  5.948 22.224 5.965 23.352 ;
     RECT  4.529 29.088 5.989 29.112 ;
     RECT  5.965 22.224 6.035 23.544 ;
     RECT  4.889 33.648 6.041 33.672 ;
     RECT  5.836 31.344 6.275 32.088 ;
     RECT  5.677 26.064 6.289 26.088 ;
     RECT  5.989 29.088 6.329 29.304 ;
     RECT  6.289 25.968 6.361 26.088 ;
     RECT  4.931 20.16 6.433 20.184 ;
     RECT  6.361 25.968 6.433 26.664 ;
     RECT  4.931 18.528 6.469 18.552 ;
     RECT  6.433 20.16 6.473 20.568 ;
     RECT  6.275 32.064 6.473 32.088 ;
     RECT  6.469 18.528 6.537 19.032 ;
     RECT  6.035 23.328 7.429 23.544 ;
     RECT  6.537 19.008 7.808 19.032 ;
     RECT  6.473 20.544 7.808 20.568 ;
     RECT  6.433 22.176 7.808 22.2 ;
     RECT  7.429 23.184 7.808 23.976 ;
     RECT  6.433 25.632 7.808 26.664 ;
     RECT  6.329 29.28 7.808 29.304 ;
     RECT  7.693 32.784 7.808 32.808 ;
     RECT  7.808 2.148 7.912 49.692 ;
     RECT  7.912 2.418 8.104 49.422 ;
     RECT  8.104 23.952 8.201 23.976 ;
     RECT  8.104 25.824 8.237 26.76 ;
     RECT  8.104 28.512 8.243 29.544 ;
     RECT  8.104 31.104 8.243 31.128 ;
     RECT  8.104 32.16 8.243 32.808 ;
     RECT  8.104 34.224 8.281 34.248 ;
     RECT  8.237 26.64 8.993 26.76 ;
     RECT  8.993 26.736 9.011 26.76 ;
     RECT  8.243 28.512 9.133 29.304 ;
     RECT  9.133 27.984 9.169 29.304 ;
     RECT  9.169 27.888 9.281 29.304 ;
     RECT  9.281 27.984 9.461 29.304 ;
     RECT  8.243 32.16 10.709 32.184 ;
     RECT  10.709 31.344 10.753 32.184 ;
     RECT  10.753 31.344 11.365 32.328 ;
     RECT  11.365 30.96 11.411 32.328 ;
     RECT  9.461 28.512 11.729 29.304 ;
     RECT  11.729 28.944 13.208 29.304 ;
     RECT  11.411 30.96 13.208 30.984 ;
     RECT  13.208 2.148 13.312 49.692 ;
     RECT  13.312 2.418 13.504 49.422 ;
     RECT  13.504 27.312 13.565 27.912 ;
     RECT  13.504 28.944 13.619 29.304 ;
     RECT  13.565 27.312 18.608 27.336 ;
     RECT  13.619 29.28 18.608 29.304 ;
     RECT  13.504 30.96 18.608 30.984 ;
     RECT  18.608 2.148 18.712 49.692 ;
     RECT  18.712 2.418 18.904 49.422 ;
     RECT  18.904 27.312 20.485 27.336 ;
     RECT  18.904 30.96 20.801 30.984 ;
     RECT  20.917 49.248 21.089 49.272 ;
     RECT  21.349 49.344 21.449 49.368 ;
     RECT  21.781 49.488 21.881 49.512 ;
     RECT  22.093 50.736 22.259 50.76 ;
     RECT  20.485 26.736 22.637 27.336 ;
     RECT  22.637 26.736 22.813 27.192 ;
     RECT  18.904 29.28 23.209 29.304 ;
     RECT  23.209 28.896 23.365 29.304 ;
     RECT  23.821 50.736 23.987 50.76 ;
     RECT  22.417 1.728 24.008 1.752 ;
     RECT  23.605 3.936 24.008 3.96 ;
     RECT  22.813 26.64 24.008 27.192 ;
     RECT  23.365 28.896 24.008 29.784 ;
     RECT  23.461 44.688 24.008 44.712 ;
     RECT  20.329 48.24 24.008 48.264 ;
     RECT  22.525 49.536 24.008 49.56 ;
     RECT  23.929 0.576 24.013 0.6 ;
     RECT  24.008 1.728 24.112 49.692 ;
     RECT  24.112 1.728 24.304 49.56 ;
     RECT  24.304 3.936 24.419 4.248 ;
     RECT  24.304 47.52 24.563 48.504 ;
     RECT  24.304 44.688 24.589 45 ;
     RECT  24.304 26.16 24.851 27.912 ;
     RECT  24.304 25.008 24.892 25.032 ;
     RECT  24.304 7.728 25.049 7.992 ;
     RECT  24.563 48.096 25.049 48.504 ;
     RECT  24.419 3.936 25.121 4.152 ;
     RECT  24.851 26.16 25.333 27.864 ;
     RECT  24.304 29.28 25.333 29.304 ;
     RECT  25.049 48.096 25.373 48.12 ;
     RECT  25.333 29.088 25.379 29.304 ;
     RECT  25.379 29.088 25.619 29.112 ;
     RECT  25.621 50.736 25.715 50.76 ;
     RECT  25.657 0.576 25.741 0.6 ;
     RECT  25.369 3.408 25.769 3.768 ;
     RECT  25.333 25.488 25.82 27.864 ;
     RECT  25.369 21.072 25.868 21.096 ;
     RECT  25.441 23.136 25.868 23.16 ;
     RECT  25.868 21.072 25.955 21.576 ;
     RECT  25.861 47.04 25.957 47.064 ;
     RECT  25.868 23.136 25.964 24.12 ;
     RECT  25.82 25.488 26.051 27.912 ;
     RECT  25.964 23.136 26.089 24.216 ;
     RECT  26.051 25.488 26.089 27.864 ;
     RECT  26.089 23.136 26.237 27.864 ;
     RECT  25.769 3.408 26.273 3.432 ;
     RECT  25.333 34.896 26.413 34.92 ;
     RECT  25.955 21.072 26.485 21.288 ;
     RECT  26.485 20.496 26.531 21.288 ;
     RECT  24.304 49.536 26.533 49.56 ;
     RECT  26.533 49.488 26.633 49.56 ;
     RECT  25.957 47.04 26.665 47.928 ;
     RECT  26.531 20.496 26.777 20.52 ;
     RECT  26.237 23.568 26.813 27.864 ;
     RECT  26.813 24.96 27.061 27.864 ;
     RECT  26.813 23.568 27.349 23.64 ;
     RECT  27.061 24.96 27.589 27.912 ;
     RECT  26.413 34.896 27.635 35.16 ;
     RECT  27.635 34.896 27.676 35.064 ;
     RECT  27.745 21.744 27.817 21.768 ;
     RECT  25.049 7.728 27.877 7.752 ;
     RECT  27.877 7.728 27.889 8.28 ;
     RECT  27.817 21.456 27.893 21.768 ;
     RECT  24.589 44.688 27.925 44.712 ;
     RECT  27.889 7.584 27.964 8.28 ;
     RECT  27.349 23.088 28.019 23.64 ;
     RECT  28.019 23.088 28.037 23.352 ;
     RECT  27.925 44.592 28.307 44.712 ;
     RECT  27.589 24.96 28.355 28.296 ;
     RECT  28.355 28.272 28.397 28.296 ;
     RECT  27.277 3.936 28.897 3.96 ;
     RECT  27.893 21.456 29.125 21.48 ;
     RECT  28.037 23.28 29.125 23.352 ;
     RECT  29.005 50.736 29.171 50.76 ;
     RECT  24.304 1.728 29.197 1.752 ;
     RECT  28.897 3.6 29.221 3.96 ;
     RECT  27.877 17.088 29.221 17.112 ;
     RECT  29.125 19.776 29.221 19.8 ;
     RECT  29.221 3.6 29.408 4.248 ;
     RECT  27.964 7.584 29.408 7.608 ;
     RECT  29.221 17.088 29.408 17.64 ;
     RECT  29.221 19.776 29.408 19.896 ;
     RECT  29.125 21.456 29.408 21.816 ;
     RECT  29.125 22.992 29.408 23.352 ;
     RECT  28.355 24.96 29.408 26.76 ;
     RECT  27.676 34.896 29.408 34.92 ;
     RECT  28.261 36.288 29.408 36.312 ;
     RECT  28.573 44.976 29.408 45 ;
     RECT  26.665 47.04 29.408 48.408 ;
     RECT  26.633 49.536 29.408 49.56 ;
     RECT  29.408 2.148 29.512 49.692 ;
     RECT  29.512 2.418 29.516 49.692 ;
     RECT  29.516 2.418 29.603 49.8 ;
     RECT  29.603 2.418 29.704 49.56 ;
     RECT  29.704 3.84 29.801 3.864 ;
     RECT  29.704 47.712 29.939 47.976 ;
     RECT  29.939 47.712 30.557 47.88 ;
     RECT  29.704 35.904 30.845 36.312 ;
     RECT  29.704 49.536 30.899 49.56 ;
     RECT  30.557 47.712 31.025 47.736 ;
     RECT  31.285 49.488 31.372 49.512 ;
     RECT  29.704 17.616 31.385 17.64 ;
     RECT  29.704 26.064 31.573 26.136 ;
     RECT  29.704 21.648 31.619 21.672 ;
     RECT  31.561 18.192 31.645 18.216 ;
     RECT  31.573 25.488 34.808 26.136 ;
     RECT  34.808 2.148 34.912 49.692 ;
     RECT  34.912 2.418 35.104 49.422 ;
     RECT  35.104 25.488 40.208 26.136 ;
     RECT  40.208 2.148 40.312 49.692 ;
     RECT  40.312 2.418 40.504 49.422 ;
     RECT  40.504 25.488 42.289 26.136 ;
     RECT  42.289 25.488 43.909 26.28 ;
     RECT  43.909 25.488 45.608 26.376 ;
     RECT  45.608 2.148 45.712 49.692 ;
     RECT  45.712 2.418 45.904 49.422 ;
     RECT  45.904 25.488 47.189 26.376 ;
     RECT  47.189 26.352 47.225 26.376 ;
     RECT  50.641 26.304 50.677 26.328 ;
     RECT  50.677 25.008 51.804 26.76 ;
    LAYER M5 ;
     RECT  22.656 0.016 29.16 1.763 ;
     RECT  2.4 2.137 2.52 2.151 ;
     RECT  7.8 2.137 7.92 2.151 ;
     RECT  13.2 2.137 13.32 2.151 ;
     RECT  18.6 2.137 18.72 2.151 ;
     RECT  29.4 2.137 29.52 2.151 ;
     RECT  34.8 2.137 34.92 2.151 ;
     RECT  40.2 2.137 40.32 2.151 ;
     RECT  45.6 2.137 45.72 2.151 ;
     RECT  24 1.763 24.312 4.213 ;
     RECT  29.4 2.151 29.712 4.213 ;
     RECT  29.28 4.213 29.712 7.619 ;
     RECT  24 4.213 24.408 8.003 ;
     RECT  29.4 7.619 29.712 17.077 ;
     RECT  27.888 7.717 27.912 17.123 ;
     RECT  6.48 18.517 6.504 19.043 ;
     RECT  4.896 18.181 4.92 19.427 ;
     RECT  29.232 17.077 29.712 19.765 ;
     RECT  4.608 20.485 4.632 20.629 ;
     RECT  4.512 20.629 4.632 21.251 ;
     RECT  26.496 20.485 26.52 21.541 ;
     RECT  4.512 21.251 4.536 22.259 ;
     RECT  29.136 19.765 29.712 23.027 ;
     RECT  7.8 2.151 8.112 23.173 ;
     RECT  7.44 23.173 8.112 23.987 ;
     RECT  27.984 23.317 28.008 24.949 ;
     RECT  24 8.003 24.312 24.997 ;
     RECT  31.584 18.181 31.608 25.523 ;
     RECT  27.984 24.949 28.104 25.765 ;
     RECT  29.232 23.027 29.712 25.765 ;
     RECT  27.984 25.765 29.712 26.101 ;
     RECT  25.92 21.541 26.52 26.579 ;
     RECT  7.8 23.987 8.112 26.725 ;
     RECT  24 24.997 24.84 26.725 ;
     RECT  25.92 26.579 26.04 26.725 ;
     RECT  27.984 26.101 29.832 26.771 ;
     RECT  24 26.725 26.04 27.157 ;
     RECT  13.2 2.151 13.512 27.301 ;
     RECT  27.984 26.771 28.344 27.395 ;
     RECT  27.984 27.395 28.104 27.877 ;
     RECT  23.376 27.157 26.04 27.923 ;
     RECT  7.8 26.725 9 28.547 ;
     RECT  13.2 27.301 13.608 29.219 ;
     RECT  6 23.125 6.024 29.269 ;
     RECT  6 29.269 6.264 29.315 ;
     RECT  7.8 28.547 8.112 29.509 ;
     RECT  4.368 28.261 4.392 29.651 ;
     RECT  23.376 27.923 25.992 29.795 ;
     RECT  6.24 29.315 6.264 30.421 ;
     RECT  10.752 29.269 10.776 30.949 ;
     RECT  5.76 30.421 6.264 31.379 ;
     RECT  10.752 30.949 11.4 31.379 ;
     RECT  5.76 31.379 5.784 31.619 ;
     RECT  11.376 31.379 11.4 32.339 ;
     RECT  7.8 29.509 8.232 34.259 ;
     RECT  27.6 27.877 28.104 34.885 ;
     RECT  29.4 26.771 29.832 34.885 ;
     RECT  24 29.795 25.992 34.931 ;
     RECT  27.6 34.885 29.832 35.893 ;
     RECT  27.6 35.893 29.928 36.323 ;
     RECT  27.6 36.323 28.296 44.965 ;
     RECT  29.4 36.323 29.928 44.965 ;
     RECT  25.872 34.931 25.992 47.075 ;
     RECT  27.6 44.965 29.928 47.363 ;
     RECT  27.6 47.363 27.624 47.411 ;
     RECT  25.968 47.075 25.992 47.939 ;
     RECT  28.656 47.363 29.928 47.987 ;
     RECT  28.656 47.987 29.712 48.419 ;
     RECT  24 34.931 24.84 48.515 ;
     RECT  20.496 26.725 20.52 49.237 ;
     RECT  20.496 49.237 20.952 49.333 ;
     RECT  20.496 49.333 21.384 49.477 ;
     RECT  20.496 49.477 21.816 49.525 ;
     RECT  24 48.515 24.312 49.525 ;
     RECT  26.544 49.477 26.568 49.525 ;
     RECT  29.4 48.419 29.712 49.525 ;
     RECT  31.296 49.477 31.32 49.525 ;
     RECT  2.4 2.151 2.712 49.689 ;
     RECT  7.8 34.259 8.112 49.689 ;
     RECT  13.2 29.219 13.512 49.689 ;
     RECT  18.6 2.151 18.912 49.689 ;
     RECT  34.8 2.151 35.112 49.689 ;
     RECT  40.2 2.151 40.512 49.689 ;
     RECT  45.6 2.151 45.912 49.689 ;
     RECT  2.4 49.689 2.52 49.703 ;
     RECT  7.8 49.689 7.92 49.703 ;
     RECT  13.2 49.689 13.32 49.703 ;
     RECT  18.6 49.689 18.72 49.703 ;
     RECT  34.8 49.689 34.92 49.703 ;
     RECT  40.2 49.689 40.32 49.703 ;
     RECT  45.6 49.689 45.72 49.703 ;
     RECT  20.496 49.525 31.32 51.792 ;
     RECT  29.28 7.619 29.4 7.717 ;
     RECT  27.912 7.717 29.4 17.077 ;
     RECT  27.912 17.077 29.232 17.123 ;
     RECT  6.504 18.517 7.8 19.043 ;
     RECT  29.136 23.027 29.232 23.317 ;
     RECT  6.024 23.173 7.44 23.987 ;
     RECT  26.52 23.317 27.984 26.579 ;
     RECT  28.008 23.317 29.232 24.949 ;
     RECT  28.104 24.949 29.232 25.765 ;
     RECT  24.84 24.997 25.92 26.725 ;
     RECT  27.6 26.579 27.984 27.877 ;
     RECT  28.344 26.771 29.4 27.395 ;
     RECT  28.104 27.395 29.4 34.885 ;
     RECT  8.112 28.547 8.232 29.509 ;
     RECT  6 29.315 6.24 30.421 ;
     RECT  24.84 34.931 25.872 47.075 ;
     RECT  28.296 36.323 29.4 44.965 ;
     RECT  24.84 47.075 25.968 47.939 ;
     RECT  27.624 47.363 28.656 47.411 ;
     RECT  28.656 48.419 29.4 49.525 ;
     RECT  24.312 48.515 24.84 49.525 ;
  END
END dsfd_vm_static_read_v7_p
END LIBRARY
